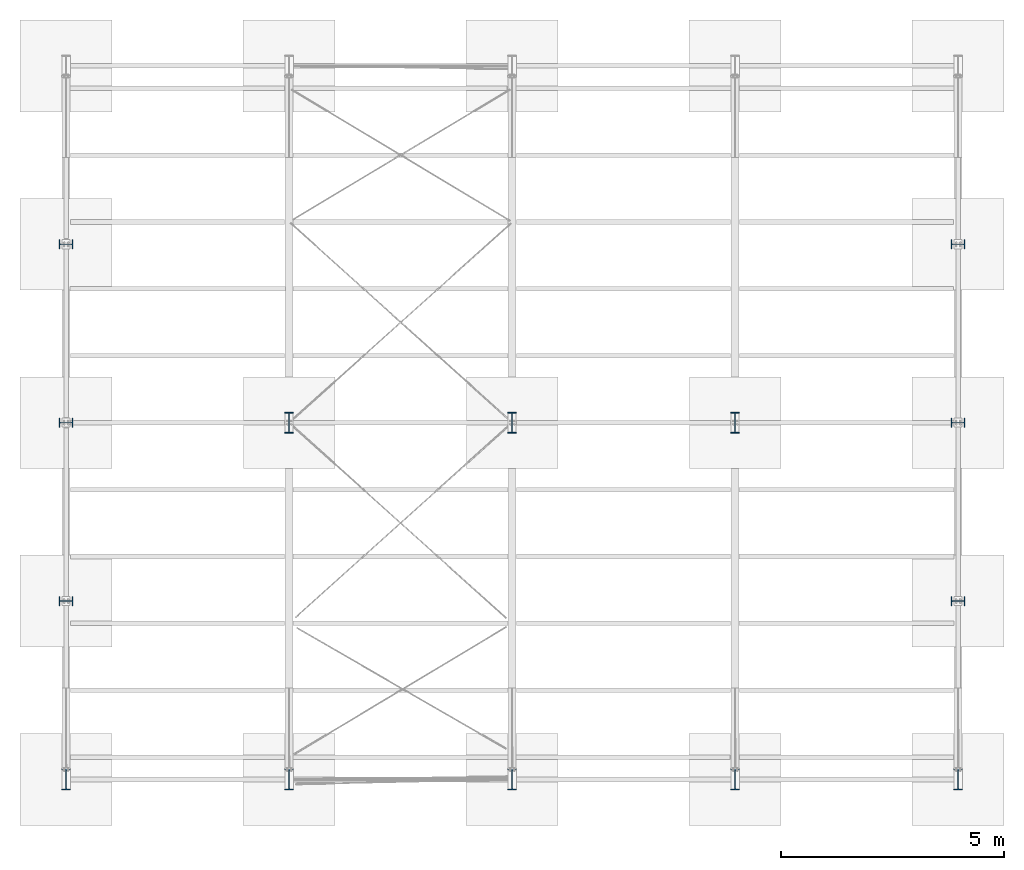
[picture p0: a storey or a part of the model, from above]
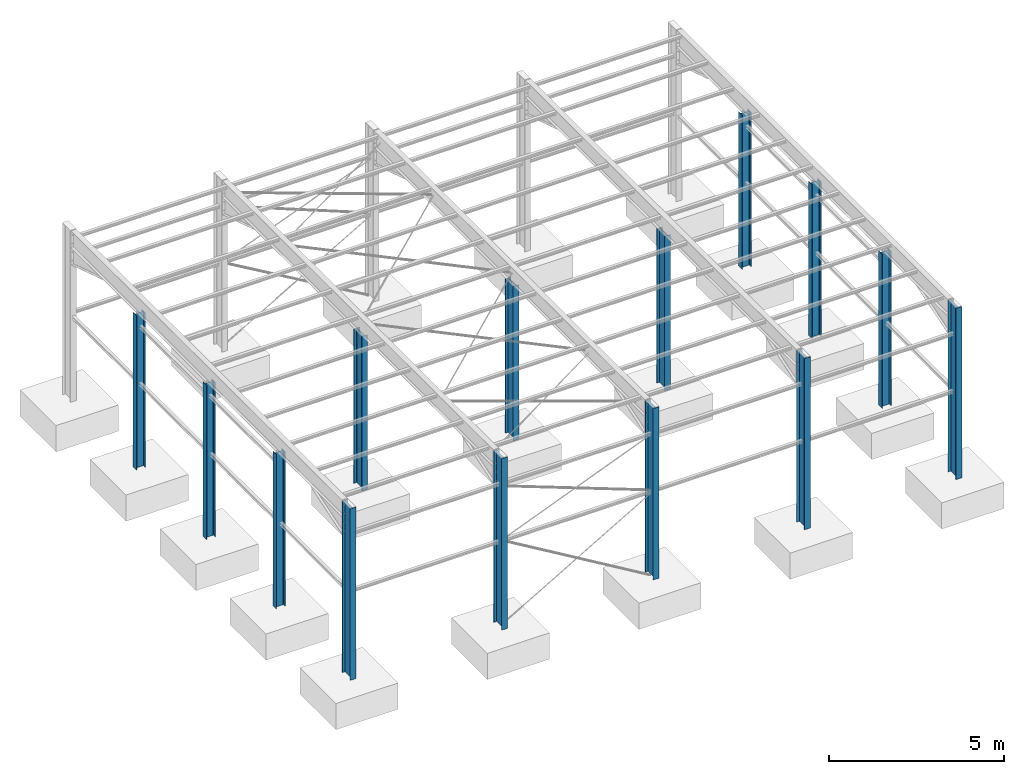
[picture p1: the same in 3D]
Properties of the parts of a building model (IFC4)

# File
Description: ViewDefinition [ReferenceView_V1.2], RevitIdentifiers [VersionGUID: 257d5f29-b7d5-4d1f-828e-4c41312c0d00, NumberOfSaves: 134], CoordinateReference [CoordinateBase: Shared Coordinates], ExchangeRequirement [Structural]
File name: REVIT 2025 Webinar RUNTHROUGH OFFICIAL.ifc
Time: 2025-12-16T14:26:53-05:00
Written by: ODA SDAI 24.11
Made in: Autodesk Revit 25.0.2.419 (ENU) - IFC 25.0.2.419

# IfcProject, 2018_01
Phase: Projekt Status

# IfcSite, Default
RefLatitude: 48, 8, 15, 359802; RefLongitude: 11, 34, 47, 783432; RefElevation: 0 ft
Pset_SiteCommon - Reference: Project Information

# IfcBeam: Round Bars:RB 1 (8)
In: Default
Type - PredefinedType: BEAM
Type - Pset_BeamCommon - IsExternal: no; LoadBearing: yes
Description: AGB ASB{0BDAC848-8ADC-4410-99BF-436318EEBB3C}; Classification: B10 Uniformat (Uniformat); Material: Steel ASTM A36
Pset_BeamCommon - Slope: 0 deg; Roll: 0 deg; Reference: RB 1
Pset_EnvironmentalImpactIndicators - Reference: RB 1; sets with these values: 2
ProfileProperties - Section: AGB ASB{0BDAC848-8ADC-4410-99BF-436318EEBB3C}
Name (Round Bars:RB 1:...) | Span (ft) = Length (ft) | NetSurfaceArea (in2) | NetVolume (m3) | SectionFamily
2572734 | 18.1667 | 692.233 | 0.00282935 | {0BDAC848-8ADC-4410-99BF-436318EEBB3C}AGB ASB
2572750 | 21.1667 | 797.42 | 0.00326025 | {0BDAC848-8ADC-4410-99BF-436318EEBB3C}AGB ASB
2572820 | 17.75 | 692.061 | 0.00282864 | {0BDAC848-8ADC-4410-99BF-436318EEBB3C}AGB ASB
2572869 | 21.3333 | 798.201 | 0.00326345 | {8E9B3756-F60C-47E6-9CB5-B6776E5EB386}AGB ASB
2572887 | 18.7292 | 692.233 | 0.00282935 | {0BDAC848-8ADC-4410-99BF-436318EEBB3C}AGB ASB
2572888 | 21.5 | 797.42 | 0.00326025 | {0BDAC848-8ADC-4410-99BF-436318EEBB3C}AGB ASB
2572889 | 18.5833 | 692.061 | 0.00282864 | {0BDAC848-8ADC-4410-99BF-436318EEBB3C}AGB ASB
2572890 | 21.7083 | 798.201 | 0.00326345 | {0BDAC848-8ADC-4410-99BF-436318EEBB3C}AGB ASB

# IfcBeam: W Shapes:W24X55 (5)
In: Default
Type - PredefinedType: BEAM
Type - Pset_BeamCommon - IsExternal: no; LoadBearing: yes
Description: BP{EC32DBDD-8F39-4A38-AAB0-52C090382C70}; Classification: B10 Uniformat (Uniformat); Material: Steel ASTM A992
Pset_BeamCommon - Reference: W24X55; Slope: 0 deg; Roll: 0 deg
Pset_EnvironmentalImpactIndicators - Reference: W24X55; sets with these values: 2
ProfileProperties - SectionFamily: {EC32DBDD-8F39-4A38-AAB0-52C090382C70}BP; Section: BP{EC32DBDD-8F39-4A38-AAB0-52C090382C70}
Name (W Shapes:W24X55:...) | Span (ft) = Length (ft) | NetSurfaceArea (in2) | NetVolume (m3)
2564772 | 51.8333 | 21209.2 | 0.076505
2564844 | 51.7292 | 21209.2 | 0.076505
2564910 | 51.75 | 21209.2 | 0.076505
2565005 | 51.7292 | 44331.9 | 0.160071
2564953 | 52.4934 | 45006.7 | 0.162509

# IfcBeam: W Shapes:W4X13 (72)
In: Default
Type - PredefinedType: BEAM
Type - Pset_BeamCommon - IsExternal: no; LoadBearing: yes
Description: BP{B9CEF4C4-659B-4EBA-904F-A6BFA4D7D305}; Classification: B10 Uniformat (Uniformat); Material: Steel ASTM A992
Pset_BeamCommon - Slope: 0 deg; Roll: 0 deg; Reference: W4X13
Pset_EnvironmentalImpactIndicators - Reference: W4X13; sets with these values: 2
ProfileProperties - SectionFamily: {B9CEF4C4-659B-4EBA-904F-A6BFA4D7D305}BP; Section: BP{B9CEF4C4-659B-4EBA-904F-A6BFA4D7D305}
Name (W Shapes:W4X13:...) | Span (ft) = Length (ft) | NetSurfaceArea (in2) | NetVolume (m3)
2526143 | 15.9167 | 4377.92 | 0.011629
2526321 | 16 | 4377.92 | 0.011629
2526471 | 16 | 4401.49 | 0.0116917
2526497 | 15.8333 | 4377.92 | 0.011629
2526596 | 12 | 3161.31 | 0.00839165
2526643 | 12.5833 | 3425.19 | 0.0090938
2526716 | 12.75 | 3448.76 | 0.00915652
2526732 | 12 | 3161.31 | 0.00839165
2526779 | 16 | 4377.92 | 0.011629
2526805 | 16.0833 | 4395.6 | 0.011676
2526849 | 15.9375 | 4372.03 | 0.0116133
2526873 | 15.8542 | 4360.24 | 0.0115819
2526911 | 11.9167 | 3184.88 | 0.00845437
2526929 | 12.5833 | 3425.19 | 0.0090938
2526979 | 12.4167 | 3401.62 | 0.00903108
2527025 | 12.0833 | 3290.95 | 0.00873661
2527203 | 16.085 | 4445.1 | 0.0118054
2527204 | 16.0417 | 4445.1 | 0.0118054
2527205 | 16.0615 | 4445.1 | 0.0118054
2527206 | 15.9945 | 4445.1 | 0.0118054
2527208 | 12.5588 | 3507.22 | 0.00931023
2527209 | 12.5432 | 3507.22 | 0.00931023
2527211 | 16.0329 | 4445.1 | 0.0118054
2527212 | 15.9695 | 4445.1 | 0.0118054
2527213 | 16.0161 | 4445.1 | 0.0118054
2527214 | 16.0859 | 4445.1 | 0.0118054
2527216 | 12.471 | 3507.22 | 0.00931023
2527217 | 12.6689 | 3507.22 | 0.00931023
2571911 | 15.75 | 4458.77 | 0.0118417
2572076 | 15.8333 | 4458.77 | 0.0118417
2572104 | 15.75 | 4458.77 | 0.0118417
2572118 | 15.75 | 4458.77 | 0.0118417
2572145 | 15.7917 | 4458.77 | 0.0118417
2572146 | 15.75 | 4379.8 | 0.0116316
2572147 | 15.8333 | 4373.91 | 0.0116183
2572148 | 15.7917 | 4458.77 | 0.0118417
2572303 | 15.75 | 4458.77 | 0.0118417
2572304 | 15.8333 | 4458.77 | 0.0118417
2572305 | 15.75 | 4458.77 | 0.0118417
2572306 | 15.75 | 4458.77 | 0.0118417
2572316 | 15.75 | 4458.77 | 0.0118417
2572317 | 15.8333 | 4458.77 | 0.0118417
2572318 | 15.75 | 4458.77 | 0.0118417
2572319 | 15.8333 | 4458.77 | 0.0118417
2572329 | 15.75 | 4458.77 | 0.0118417
2572330 | 15.8333 | 4458.77 | 0.0118417
2572331 | 15.75 | 4458.77 | 0.0118417
2572332 | 15.8333 | 4458.77 | 0.0118417
2572346 | 15.75 | 4458.77 | 0.0118417
2572347 | 15.8333 | 4458.77 | 0.0118417
2572348 | 15.75 | 4458.77 | 0.0118417
2572349 | 15.8333 | 4458.77 | 0.0118417
2572419 | 15.75 | 4368.02 | 0.0116026
2572420 | 15.8333 | 4458.77 | 0.0118417
2572421 | 15.75 | 4458.77 | 0.0118417
2572422 | 15.8125 | 4458.77 | 0.0118417
2572434 | 15.75 | 4458.77 | 0.0118417
2572435 | 15.8333 | 4458.77 | 0.0118417
2572436 | 15.75 | 4458.77 | 0.0118417
2572437 | 15.8333 | 4458.77 | 0.0118417
2572438 | 15.75 | 4368.02 | 0.0116026
2572439 | 15.8333 | 4458.77 | 0.0118417
2572440 | 15.75 | 4458.77 | 0.0118417
2572441 | 15.75 | 4458.77 | 0.0118417
2572442 | 15.8333 | 4379.8 | 0.0116316
2572443 | 15.8333 | 4458.77 | 0.0118417
2572444 | 15.75 | 4458.77 | 0.0118417
2572445 | 15.75 | 4458.77 | 0.0118417
2572446 | 15.75 | 4458.77 | 0.0118417
2572447 | 15.8333 | 4458.77 | 0.0118417
2572448 | 15.75 | 4458.77 | 0.0118417
2572449 | 15.75 | 4458.77 | 0.0118417

# IfcColumn: W Shapes-Column:W12X40 (6)
In: Default
Type - PredefinedType: COLUMN; Material: Steel ASTM A992
Type - Pset_ColumnCommon - IsExternal: no; LoadBearing: yes
Description: BP{5F7675C8-A018-401B-841C-6AB59980B69C}; Classification: B10 Uniformat (Uniformat)
Pset_ColumnCommon - Reference: W12X40
Pset_EnvironmentalImpactIndicators - Reference: W12X40; sets with these values: 2
Qto_ColumnBaseQuantities - Length: 19.685 ft; NetSurfaceArea: 12869.7 in2; NetVolume: 0.0451988 m3
ProfileProperties - SectionFamily: {5FFC2389-D0AE-4B68-A1EB-C48F181580E0}BP; Section: BP{5F7675C8-A018-401B-841C-6AB59980B69C}
Name (W Shapes-Column:W12X40:...)
2521363
2522051
2522128
2522207
2522318
2522393

# IfcColumn: W Shapes-Column:W18X65 (13)
In: Default
Type - PredefinedType: COLUMN; Material: Steel ASTM A992
Type - Pset_ColumnCommon - IsExternal: no; LoadBearing: yes
Description: BP{5FFC2389-D0AE-4B68-A1EB-C48F181580E0}; Classification: B10 Uniformat (Uniformat)
Pset_ColumnCommon - Reference: W18X65
Pset_EnvironmentalImpactIndicators - Reference: W18X65; sets with these values: 2
Qto_ColumnBaseQuantities - Length: 19.685 ft; NetSurfaceArea: 15528 in2; NetVolume: 0.0740422 m3
ProfileProperties - SectionFamily: {5FFC2389-D0AE-4B68-A1EB-C48F181580E0}BP; Section: BP{5FFC2389-D0AE-4B68-A1EB-C48F181580E0}
Name (W Shapes-Column:W18X65:...)
2520878
2520965
2521026
2521109
2519903
2520181
2520254
2520431
2520482
2520589
2564533
2564545
2564557

# IfcMechanicalFastener: Bolt (9)
In: Default
NominalDiameter: 0.0625 ft; NominalLength: 0.1875 ft

# IfcMechanicalFastener: Bolt#1 (11)
In: Default
NominalDiameter: 0.0625 ft; NominalLength: 0.229167 ft

# IfcMechanicalFastener: Bolt#2 (11)
In: Default
NominalDiameter: 0.0625 ft; NominalLength: 0.229167 ft

# IfcMechanicalFastener: Bolt#3 (11)
In: Default
NominalDiameter: 0.0625 ft; NominalLength: 0.229167 ft

# IfcMechanicalFastener: Bolt#4 (11)
In: Default
NominalDiameter: 0.0625 ft; NominalLength: 0.229167 ft

# IfcMechanicalFastener: Bolt#5 (11)
In: Default
NominalDiameter: 0.0625 ft; NominalLength: 0.229167 ft

# IfcMechanicalFastener: Bolt#6 (11)
In: Default
NominalDiameter: 0.0625 ft; NominalLength: 0.229167 ft

# IfcMechanicalFastener: Bolt#7 (11)
In: Default
NominalDiameter: 0.0625 ft; NominalLength: 0.229167 ft

# IfcMechanicalFastener: Bolt#8 (11)
In: Default
NominalDiameter: 0.0625 ft; NominalLength: 0.229167 ft

# IfcMember: Haunch (11)
In: Default
Description: BP{EC32DBDD-8F39-4A38-AAB0-52C090382C70}
ProfileProperties - SectionFamily: {EC32DBDD-8F39-4A38-AAB0-52C090382C70}BP; Section: BP{EC32DBDD-8F39-4A38-AAB0-52C090382C70}

# IfcMember: Round Bars:RB 1 (8)
In: Default
Type - PredefinedType: MEMBER; Material: Steel ASTM A36
Type - Pset_MemberCommon - IsExternal: no; LoadBearing: yes
Description: AGB ASB{0BDAC848-8ADC-4410-99BF-436318EEBB3C}; Classification: B10 Uniformat (Uniformat)
Pset_EnvironmentalImpactIndicators - Reference: RB 1
Pset_MemberCommon - Roll: 0 deg; Reference: RB 1
ProfileProperties - SectionFamily: {8E9B3756-F60C-47E6-9CB5-B6776E5EB386}AGB ASB; Section: AGB ASB{0BDAC848-8ADC-4410-99BF-436318EEBB3C}
Name (Round Bars:RB 1:...) | Span (ft) = Length (ft) | Slope (deg) | NetSurfaceArea (in2) | NetVolume (m3)
2557057 | 18.6667 | 29.5693 | 681.892 | 0.00277743
2557153 | 18.3542 | 31.2614 | 689.523 | 0.00280858
2557347 | 17.9167 | 30.2369 | 656.405 | 0.00267338
2557348 | 17.8292 | 30.3927 | 648.842 | 0.00264251
2578470 | 16.9628 | 20.7672 | 597.973 | 0.00243484
2578548 | 17 | 21.6811 | 625.061 | 0.00254542
2578592 | 16.6775 | 21.7478 | 639.823 | 0.00260569
2578593 | 16.7611 | 21.7309 | 611.135 | 0.00248857

# IfcPlate: Coverplate (11)
In: Default
Description: -; Material: Dachdeckung - Blechdach 15 ft
Pset_PlateCommon - Reference: Not defined; IsExternal: no; LoadBearing: no

# IfcPlate: Endplate (20)
In: Default
Description: -
Pset_PlateCommon - Reference: Not defined; IsExternal: no; LoadBearing: no
Name | Material
11 x Endplate | Dachdeckung - Blechdach 20 ft
9 x Endplate | Dachdeckung - Blechdach 12.7 ft

# IfcSlab: Pile Cap-Rectangular:81" x 81" x 36" (19)
In: Default
Type - PredefinedType: BASESLAB; Material: Concrete, Cast-in-Place gray
Type - Pset_SlabCommon - IsExternal: no
Classification: A1010100 Uniformat (Uniformat)
Pset_EnvironmentalImpactIndicators - Reference: 81" x 81" x 36"; sets with these values: 2
Pset_SlabCommon - Reference: 81" x 81" x 36"
Qto_SlabBaseQuantities - Width: 6.75 ft; Length: 6.75 ft; Depth: 3 ft; Perimeter: 27 ft; GrossArea: 6561 in2; NetArea: 6561 in2; GrossVolume: 3.87056 m3; NetVolume: 3.87056 m3
Name (Pile Cap-Rectangular:81" x 81" x 36":...)
2543343
2543812
2543825
2543834
2543845
2543856
2543869
2543880
2543893
2543906
2544030
2544391
2544400
2544413
2544422
2544433
2564534
2564546
2564558
